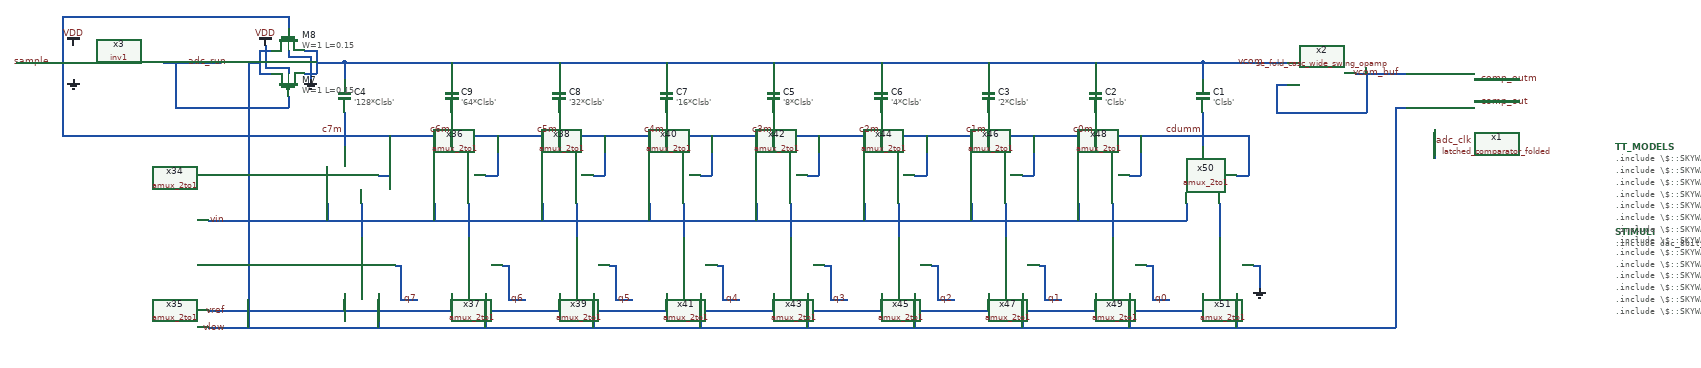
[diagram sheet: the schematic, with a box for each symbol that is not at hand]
v {xschem version=2.9.9 file_version=1.2 

* Copyright 2020 Stefan Frederik Schippers
* 
* Licensed under the Apache License, Version 2.0 (the "License");
* you may not use this file except in compliance with the License.
* You may obtain a copy of the License at
*
*     https://www.apache.org/licenses/LICENSE-2.0
*
* Unless required by applicable law or agreed to in writing, software
* distributed under the License is distributed on an "AS IS" BASIS,
* WITHOUT WARRANTIES OR CONDITIONS OF ANY KIND, either express or implied.
* See the License for the specific language governing permissions and
* limitations under the License.

}
G {}
K {}
V {}
S {}
E {}
N 250 -790 250 -760 { lab=vcom}
N 250 -790 1770 -790 { lab=vcom}
N 1770 -790 1770 -760 { lab=vcom}
N 1580 -790 1580 -760 { lab=vcom}
N 1390 -790 1390 -760 { lab=vcom}
N 1200 -790 1200 -760 { lab=vcom}
N 1010 -790 1010 -760 { lab=vcom}
N 820 -790 820 -760 { lab=vcom}
N 630 -790 630 -760 { lab=vcom}
N 440 -790 440 -760 { lab=vcom}
N 1770 -790 1920 -790 { lab=vcom}
N 100 -810 100 -790 { lab=vlow}
N 100 -810 120 -810 { lab=vlow}
N 100 -790 100 -770 { lab=vlow}
N 100 -770 120 -770 { lab=vlow}
N 180 -810 200 -810 { lab=vcom}
N 200 -810 200 -770 { lab=vcom}
N 180 -770 200 -770 { lab=vcom}
N 150 -780 150 -770 { lab=VDD}
N 150 -810 150 -800 { lab=GND}
N 200 -790 250 -790 { lab=vcom}
N 150 -800 190 -800 { lab=GND}
N 190 -800 190 -760 { lab=GND}
N 110 -820 110 -780 { lab=VDD}
N 110 -780 150 -780 { lab=VDD}
N 80 -790 100 -790 { lab=vlow}
N 2250 -720 2330 -720 { lab=comp_out}
N -330 -790 -230 -790 { lab=sample}
N -70 -790 30 -790 { lab=adc_run}
N -250 -790 -250 -660 { lab=sample}
N -250 -660 1850 -660 { lab=sample}
N 280 -540 280 -480 { lab=#net1}
N 470 -540 470 -480 { lab=#net2}
N 660 -540 660 -480 { lab=#net3}
N 850 -540 850 -480 { lab=#net4}
N 1040 -540 1040 -480 { lab=#net5}
N 1230 -540 1230 -480 { lab=#net6}
N 1420 -540 1420 -480 { lab=#net7}
N 1610 -540 1610 -480 { lab=#net8}
N 1800 -540 1800 -480 { lab=#net9}
N 10 -510 1740 -510 { lab=vin}
N 1740 -540 1740 -510 { lab=vin}
N 220 -540 220 -510 { lab=vin}
N 410 -540 410 -510 { lab=vin}
N 600 -540 600 -510 { lab=vin}
N 790 -540 790 -510 { lab=vin}
N 980 -540 980 -510 { lab=vin}
N 1170 -540 1170 -510 { lab=vin}
N 1360 -540 1360 -510 { lab=vin}
N 1550 -540 1550 -510 { lab=vin}
N 1770 -380 1770 -350 { lab=vref}
N 250 -380 250 -350 { lab=vref}
N 440 -380 440 -350 { lab=vref}
N 630 -380 630 -350 { lab=vref}
N 820 -380 820 -350 { lab=vref}
N 1010 -380 1010 -350 { lab=vref}
N 1200 -380 1200 -350 { lab=vref}
N 1390 -380 1390 -350 { lab=vref}
N 1580 -380 1580 -350 { lab=vref}
N 10 -350 1770 -350 { lab=vref}
N 1830 -380 1830 -320 { lab=vlow}
N 1640 -380 1640 -320 { lab=vlow}
N 1450 -380 1450 -320 { lab=vlow}
N 1260 -380 1260 -320 { lab=vlow}
N 1070 -380 1070 -320 { lab=vlow}
N 880 -380 880 -320 { lab=vlow}
N 690 -380 690 -320 { lab=vlow}
N 500 -380 500 -320 { lab=vlow}
N 310 -380 310 -320 { lab=vlow}
N 80 -790 80 -320 { lab=vlow}
N 250 -700 250 -640 { lab=c7m}
N 440 -700 440 -640 { lab=c6m}
N 630 -700 630 -640 { lab=c5m}
N 820 -700 820 -640 { lab=c4m}
N 1010 -700 1010 -640 { lab=c3m}
N 1200 -700 1200 -640 { lab=c2m}
N 1390 -700 1390 -640 { lab=c1m}
N 1580 -700 1580 -640 { lab=c0m}
N 1770 -700 1770 -640 { lab=cdumm}
N 310 -590 330 -590 { lab=sample}
N 330 -660 330 -590 { lab=sample}
N 500 -590 520 -590 { lab=sample}
N 520 -660 520 -590 { lab=sample}
N 690 -590 710 -590 { lab=sample}
N 710 -660 710 -590 { lab=sample}
N 880 -590 900 -590 { lab=sample}
N 900 -660 900 -590 { lab=sample}
N 1070 -590 1090 -590 { lab=sample}
N 1090 -660 1090 -590 { lab=sample}
N 1260 -590 1280 -590 { lab=sample}
N 1280 -660 1280 -590 { lab=sample}
N 1450 -590 1470 -590 { lab=sample}
N 1470 -660 1470 -590 { lab=sample}
N 1640 -590 1660 -590 { lab=sample}
N 1660 -660 1660 -590 { lab=sample}
N 1830 -590 1850 -590 { lab=sample}
N 1850 -660 1850 -590 { lab=sample}
N 350 -370 380 -370 { lab=q7}
N 540 -370 570 -370 { lab=q6}
N 730 -370 760 -370 { lab=q5}
N 920 -370 950 -370 { lab=q4}
N 1110 -370 1140 -370 { lab=q3}
N 1300 -370 1330 -370 { lab=q2}
N 1490 -370 1520 -370 { lab=q1}
N 1680 -370 1710 -370 { lab=q0}
N 340 -430 350 -430 { lab=q7}
N 350 -430 350 -370 { lab=q7}
N 530 -430 540 -430 { lab=q6}
N 540 -430 540 -370 { lab=q6}
N 720 -430 730 -430 { lab=q5}
N 730 -430 730 -370 { lab=q5}
N 910 -430 920 -430 { lab=q4}
N 920 -430 920 -370 { lab=q4}
N 1100 -430 1110 -430 { lab=q3}
N 1110 -430 1110 -370 { lab=q3}
N 1290 -430 1300 -430 { lab=q2}
N 1300 -430 1300 -370 { lab=q2}
N 1480 -430 1490 -430 { lab=q1}
N 1490 -430 1490 -370 { lab=q1}
N 1670 -430 1680 -430 { lab=q0}
N 1680 -430 1680 -370 { lab=q0}
N -250 -870 -250 -790 { lab=sample}
N -250 -870 150 -870 { lab=sample}
N 150 -870 150 -850 { lab=sample}
N -50 -790 -50 -710 { lab=adc_run}
N -50 -710 150 -710 { lab=adc_run}
N 150 -730 150 -710 { lab=adc_run}
N 1860 -430 1870 -430 { lab=GND}
N 1870 -430 1870 -390 { lab=GND}
N 2110 -710 2130 -710 { lab=vlow}
N 2180 -670 2180 -620 { lab=adc_clk}
N 2250 -760 2330 -760 { lab=comp_outm}
N 1900 -750 1920 -750 { lab=vcom_buf}
N 1900 -750 1900 -700 { lab=vcom_buf}
N 2040 -770 2130 -770 { lab=vcom_buf}
N 1900 -700 2060 -700 { lab=vcom_buf}
N 2060 -770 2060 -700 { lab=vcom_buf}
N 2110 -710 2110 -320 { lab=vlow}
N 10 -320 2110 -320 { lab=vlow}
C {devices/title.sym} 160 -30 0 0 {name=l1 author="Nikhil Poole"}
C {devices/code.sym} 2500 -490 0 0 {name=STIMULI 
only_toplevel=true
place=end
value=".include dac_8bit_commands.spice"}
C {devices/code.sym} 2500 -640 0 0 {name=TT_MODELS
only_toplevel=true
format="tcleval( @value )"
value="
.include \\\\$::SKYWATER_MODELS\\\\/cells/nfet_01v8/sky130_fd_pr__nfet_01v8__tt.corner.spice
.include \\\\$::SKYWATER_MODELS\\\\/cells/nfet_01v8_lvt/sky130_fd_pr__nfet_01v8_lvt__tt.corner.spice
.include \\\\$::SKYWATER_MODELS\\\\/cells/pfet_01v8/sky130_fd_pr__pfet_01v8__tt.corner.spice
.include \\\\$::SKYWATER_MODELS\\\\/cells/nfet_03v3_nvt/sky130_fd_pr__nfet_03v3_nvt__tt.corner.spice
.include \\\\$::SKYWATER_MODELS\\\\/cells/nfet_05v0_nvt/sky130_fd_pr__nfet_05v0_nvt__tt.corner.spice
.include \\\\$::SKYWATER_MODELS\\\\/cells/esd_nfet_01v8/sky130_fd_pr__esd_nfet_01v8__tt.corner.spice
.include \\\\$::SKYWATER_MODELS\\\\/cells/pfet_01v8_lvt/sky130_fd_pr__pfet_01v8_lvt__tt.corner.spice
.include \\\\$::SKYWATER_MODELS\\\\/cells/pfet_01v8_hvt/sky130_fd_pr__pfet_01v8_hvt__tt.corner.spice
.include \\\\$::SKYWATER_MODELS\\\\/cells/esd_pfet_g5v0d10v5/sky130_fd_pr__esd_pfet_g5v0d10v5__tt.corner.spice
.include \\\\$::SKYWATER_MODELS\\\\/cells/pfet_g5v0d10v5/sky130_fd_pr__pfet_g5v0d10v5__tt.corner.spice
.include \\\\$::SKYWATER_MODELS\\\\/cells/pfet_g5v0d16v0/sky130_fd_pr__pfet_g5v0d16v0__tt.corner.spice
.include \\\\$::SKYWATER_MODELS\\\\/cells/nfet_g5v0d10v5/sky130_fd_pr__nfet_g5v0d10v5__tt.corner.spice
.include \\\\$::SKYWATER_MODELS\\\\/cells/nfet_g5v0d16v0/sky130_fd_pr__nfet_g5v0d16v0__tt_discrete.corner.spice
.include \\\\$::SKYWATER_MODELS\\\\/cells/esd_nfet_g5v0d10v5/sky130_fd_pr__esd_nfet_g5v0d10v5__tt.corner.spice
.include \\\\$::SKYWATER_MODELS\\\\/models/corners/tt/nonfet.spice
* Mismatch parameters
.include \\\\$::SKYWATER_MODELS\\\\/cells/nfet_01v8/sky130_fd_pr__nfet_01v8__mismatch.corner.spice
.include \\\\$::SKYWATER_MODELS\\\\/cells/pfet_01v8/sky130_fd_pr__pfet_01v8__mismatch.corner.spice
.include \\\\$::SKYWATER_MODELS\\\\/cells/nfet_01v8_lvt/sky130_fd_pr__nfet_01v8_lvt__mismatch.corner.spice
.include \\\\$::SKYWATER_MODELS\\\\/cells/pfet_01v8_lvt/sky130_fd_pr__pfet_01v8_lvt__mismatch.corner.spice
.include \\\\$::SKYWATER_MODELS\\\\/cells/pfet_01v8_hvt/sky130_fd_pr__pfet_01v8_hvt__mismatch.corner.spice
.include \\\\$::SKYWATER_MODELS\\\\/cells/nfet_g5v0d10v5/sky130_fd_pr__nfet_g5v0d10v5__mismatch.corner.spice
.include \\\\$::SKYWATER_MODELS\\\\/cells/pfet_g5v0d10v5/sky130_fd_pr__pfet_g5v0d10v5__mismatch.corner.spice
.include \\\\$::SKYWATER_MODELS\\\\/cells/nfet_05v0_nvt/sky130_fd_pr__nfet_05v0_nvt__mismatch.corner.spice
.include \\\\$::SKYWATER_MODELS\\\\/cells/nfet_03v3_nvt/sky130_fd_pr__nfet_03v3_nvt__mismatch.corner.spice
* Resistor\\\\$::SKYWATER_MODELS\\\\/Capacitor
.include \\\\$::SKYWATER_MODELS\\\\/models/r+c/res_typical__cap_typical.spice
.include \\\\$::SKYWATER_MODELS\\\\/models/r+c/res_typical__cap_typical__lin.spice
* Special cells
.include \\\\$::SKYWATER_MODELS\\\\/models/corners/tt/specialized_cells.spice
* All models
.include \\\\$::SKYWATER_MODELS\\\\/models/all.spice
* Corner
.include \\\\$::SKYWATER_MODELS\\\\/models/corners/tt/rf.spice
"}
C {devices/capa.sym} 1770 -730 0 0 {name=C1
m=1
value='Clsb'
footprint=1206
device="ceramic capacitor"}
C {devices/capa.sym} 1580 -730 0 0 {name=C2
m=1
value='Clsb'
footprint=1206
device="ceramic capacitor"}
C {devices/capa.sym} 1390 -730 0 0 {name=C3
m=1
value='2*Clsb'
footprint=1206
device="ceramic capacitor"}
C {devices/capa.sym} 250 -730 0 0 {name=C4
m=1
value='128*Clsb'
footprint=1206
device="ceramic capacitor"}
C {devices/capa.sym} 1010 -730 0 0 {name=C5
m=1
value='8*Clsb'
footprint=1206
device="ceramic capacitor"}
C {devices/capa.sym} 1200 -730 0 0 {name=C6
m=1
value='4*Clsb'
footprint=1206
device="ceramic capacitor"}
C {devices/capa.sym} 820 -730 0 0 {name=C7
m=1
value='16*Clsb'
footprint=1206
device="ceramic capacitor"}
C {devices/capa.sym} 630 -730 0 0 {name=C8
m=1
value='32*Clsb'
footprint=1206
device="ceramic capacitor"}
C {devices/capa.sym} 440 -730 0 0 {name=C9
m=1
value='64*Clsb'
footprint=1206
device="ceramic capacitor"}
C {sky130_fd_pr/pfet_01v8_hvt.sym} 150 -750 3 0 {name=M7
L=0.15
W=1
nf=1
mult=1
ad="'int((nf+1)/2) * W/nf * 0.29'" 
pd="'2*int((nf+1)/2) * (W/nf + 0.29)'"
as="'int((nf+2)/2) * W/nf * 0.29'" 
ps="'2*int((nf+2)/2) * (W/nf + 0.29)'"
nrd="'0.29 / W'" nrs="'0.29 / W'"
sa=0 sb=0 sd=0
model=pfet_01v8_hvt
spiceprefix=X
}
C {sky130_fd_pr/nfet_01v8.sym} 150 -830 3 1 {name=M8
L=0.15
W=1
nf=1 
mult=1
ad="'int((nf+1)/2) * W/nf * 0.29'" 
pd="'2*int((nf+1)/2) * (W/nf + 0.29)'"
as="'int((nf+2)/2) * W/nf * 0.29'" 
ps="'2*int((nf+2)/2) * (W/nf + 0.29)'"
nrd="'0.29 / W'" nrs="'0.29 / W'"
sa=0 sb=0 sd=0
model=nfet_01v8
spiceprefix=X
}
C {devices/lab_wire.sym} -30 -790 0 1 {name=l123 sig_type=std_logic lab=adc_run}
C {devices/lab_wire.sym} 2260 -720 0 1 {name=l124 sig_type=std_logic lab=comp_out}
C {devices/lab_wire.sym} -270 -790 0 0 {name=l125 sig_type=std_logic lab=sample}
C {/home/users/nhpoole/ee272b/ee272b_mixed_signal_mmwave_accelerator/designs/amux_2to1.sym} 250 -590 3 0 {name=x34 M=1}
C {/home/users/nhpoole/ee272b/ee272b_mixed_signal_mmwave_accelerator/designs/amux_2to1.sym} 280 -430 3 0 {name=x35 M=1}
C {devices/lab_wire.sym} 40 -510 0 0 {name=l7 sig_type=std_logic lab=vin}
C {/home/users/nhpoole/ee272b/ee272b_mixed_signal_mmwave_accelerator/designs/amux_2to1.sym} 440 -590 3 0 {name=x36 M=1}
C {/home/users/nhpoole/ee272b/ee272b_mixed_signal_mmwave_accelerator/designs/amux_2to1.sym} 470 -430 3 0 {name=x37 M=1}
C {/home/users/nhpoole/ee272b/ee272b_mixed_signal_mmwave_accelerator/designs/amux_2to1.sym} 630 -590 3 0 {name=x38 M=1}
C {/home/users/nhpoole/ee272b/ee272b_mixed_signal_mmwave_accelerator/designs/amux_2to1.sym} 660 -430 3 0 {name=x39 M=1}
C {/home/users/nhpoole/ee272b/ee272b_mixed_signal_mmwave_accelerator/designs/amux_2to1.sym} 820 -590 3 0 {name=x40 M=1}
C {/home/users/nhpoole/ee272b/ee272b_mixed_signal_mmwave_accelerator/designs/amux_2to1.sym} 850 -430 3 0 {name=x41 M=1}
C {/home/users/nhpoole/ee272b/ee272b_mixed_signal_mmwave_accelerator/designs/amux_2to1.sym} 1010 -590 3 0 {name=x42 M=1}
C {/home/users/nhpoole/ee272b/ee272b_mixed_signal_mmwave_accelerator/designs/amux_2to1.sym} 1040 -430 3 0 {name=x43 M=1}
C {/home/users/nhpoole/ee272b/ee272b_mixed_signal_mmwave_accelerator/designs/amux_2to1.sym} 1200 -590 3 0 {name=x44 M=1}
C {/home/users/nhpoole/ee272b/ee272b_mixed_signal_mmwave_accelerator/designs/amux_2to1.sym} 1230 -430 3 0 {name=x45 M=1}
C {/home/users/nhpoole/ee272b/ee272b_mixed_signal_mmwave_accelerator/designs/amux_2to1.sym} 1390 -590 3 0 {name=x46 M=1}
C {/home/users/nhpoole/ee272b/ee272b_mixed_signal_mmwave_accelerator/designs/amux_2to1.sym} 1420 -430 3 0 {name=x47 M=1}
C {/home/users/nhpoole/ee272b/ee272b_mixed_signal_mmwave_accelerator/designs/amux_2to1.sym} 1580 -590 3 0 {name=x48 M=1}
C {/home/users/nhpoole/ee272b/ee272b_mixed_signal_mmwave_accelerator/designs/amux_2to1.sym} 1610 -430 3 0 {name=x49 M=1}
C {/home/users/nhpoole/ee272b/ee272b_mixed_signal_mmwave_accelerator/designs/amux_2to1.sym} 1770 -590 3 0 {name=x50 M=1}
C {/home/users/nhpoole/ee272b/ee272b_mixed_signal_mmwave_accelerator/designs/amux_2to1.sym} 1800 -430 3 0 {name=x51 M=1}
C {devices/lab_wire.sym} 40 -350 0 0 {name=l39 sig_type=std_logic lab=vref}
C {devices/lab_wire.sym} 40 -320 0 0 {name=l40 sig_type=std_logic lab=vlow}
C {devices/lab_wire.sym} 380 -370 0 0 {name=l41 sig_type=std_logic lab=q7}
C {devices/lab_wire.sym} 570 -370 0 0 {name=l42 sig_type=std_logic lab=q6}
C {devices/lab_wire.sym} 760 -370 0 0 {name=l43 sig_type=std_logic lab=q5}
C {devices/lab_wire.sym} 950 -370 0 0 {name=l44 sig_type=std_logic lab=q4}
C {devices/lab_wire.sym} 1140 -370 0 0 {name=l45 sig_type=std_logic lab=q3}
C {devices/lab_wire.sym} 1330 -370 0 0 {name=l46 sig_type=std_logic lab=q2}
C {devices/lab_wire.sym} 1520 -370 0 0 {name=l47 sig_type=std_logic lab=q1}
C {devices/lab_wire.sym} 1710 -370 0 0 {name=l48 sig_type=std_logic lab=q0}
C {devices/gnd.sym} 1870 -390 0 1 {name=l2 lab=GND}
C {devices/lab_wire.sym} 250 -670 0 0 {name=l5 sig_type=std_logic lab=c7m}
C {devices/lab_wire.sym} 440 -670 0 0 {name=l8 sig_type=std_logic lab=c6m}
C {devices/lab_wire.sym} 630 -670 0 0 {name=l10 sig_type=std_logic lab=c5m}
C {devices/lab_wire.sym} 820 -670 0 0 {name=l12 sig_type=std_logic lab=c4m}
C {devices/lab_wire.sym} 1010 -670 0 0 {name=l13 sig_type=std_logic lab=c3m}
C {devices/lab_wire.sym} 1200 -670 0 0 {name=l16 sig_type=std_logic lab=c2m}
C {devices/lab_wire.sym} 1390 -670 0 0 {name=l19 sig_type=std_logic lab=c1m}
C {devices/lab_wire.sym} 1580 -670 0 0 {name=l22 sig_type=std_logic lab=c0m}
C {devices/lab_wire.sym} 1770 -670 0 0 {name=l25 sig_type=std_logic lab=cdumm}
C {devices/lab_wire.sym} 1880 -790 0 0 {name=l26 sig_type=std_logic lab=vcom}
C {devices/lab_wire.sym} 2180 -650 2 0 {name=l4 sig_type=std_logic lab=adc_clk}
C {devices/lab_wire.sym} 2260 -760 0 1 {name=l6 sig_type=std_logic lab=comp_outm}
C {/home/users/nhpoole/ee272b/ee272b_mixed_signal_mmwave_accelerator/designs/latched_comparator_folded.sym} 2190 -740 2 1 {name=x1}
C {/home/users/nhpoole/ee272b/ee272b_mixed_signal_mmwave_accelerator/designs/se_fold_casc_wide_swing_opamp.sym} 1970 -770 0 0 {name=x2}
C {devices/lab_wire.sym} 2120 -770 0 0 {name=l3 sig_type=std_logic lab=vcom_buf}
C {/home/users/nhpoole/ee272b/ee272b_mixed_signal_mmwave_accelerator/designs/inv1.sym} -180 -790 0 0 {name=x3}
C {devices/gnd.sym} -230 -760 0 1 {name=l17 lab=GND}
C {devices/vdd.sym} -230 -820 0 0 {name=l11 lab=VDD}
C {devices/vdd.sym} 110 -820 0 0 {name=l9 lab=VDD}
C {devices/gnd.sym} 190 -760 0 1 {name=l14 lab=GND}
